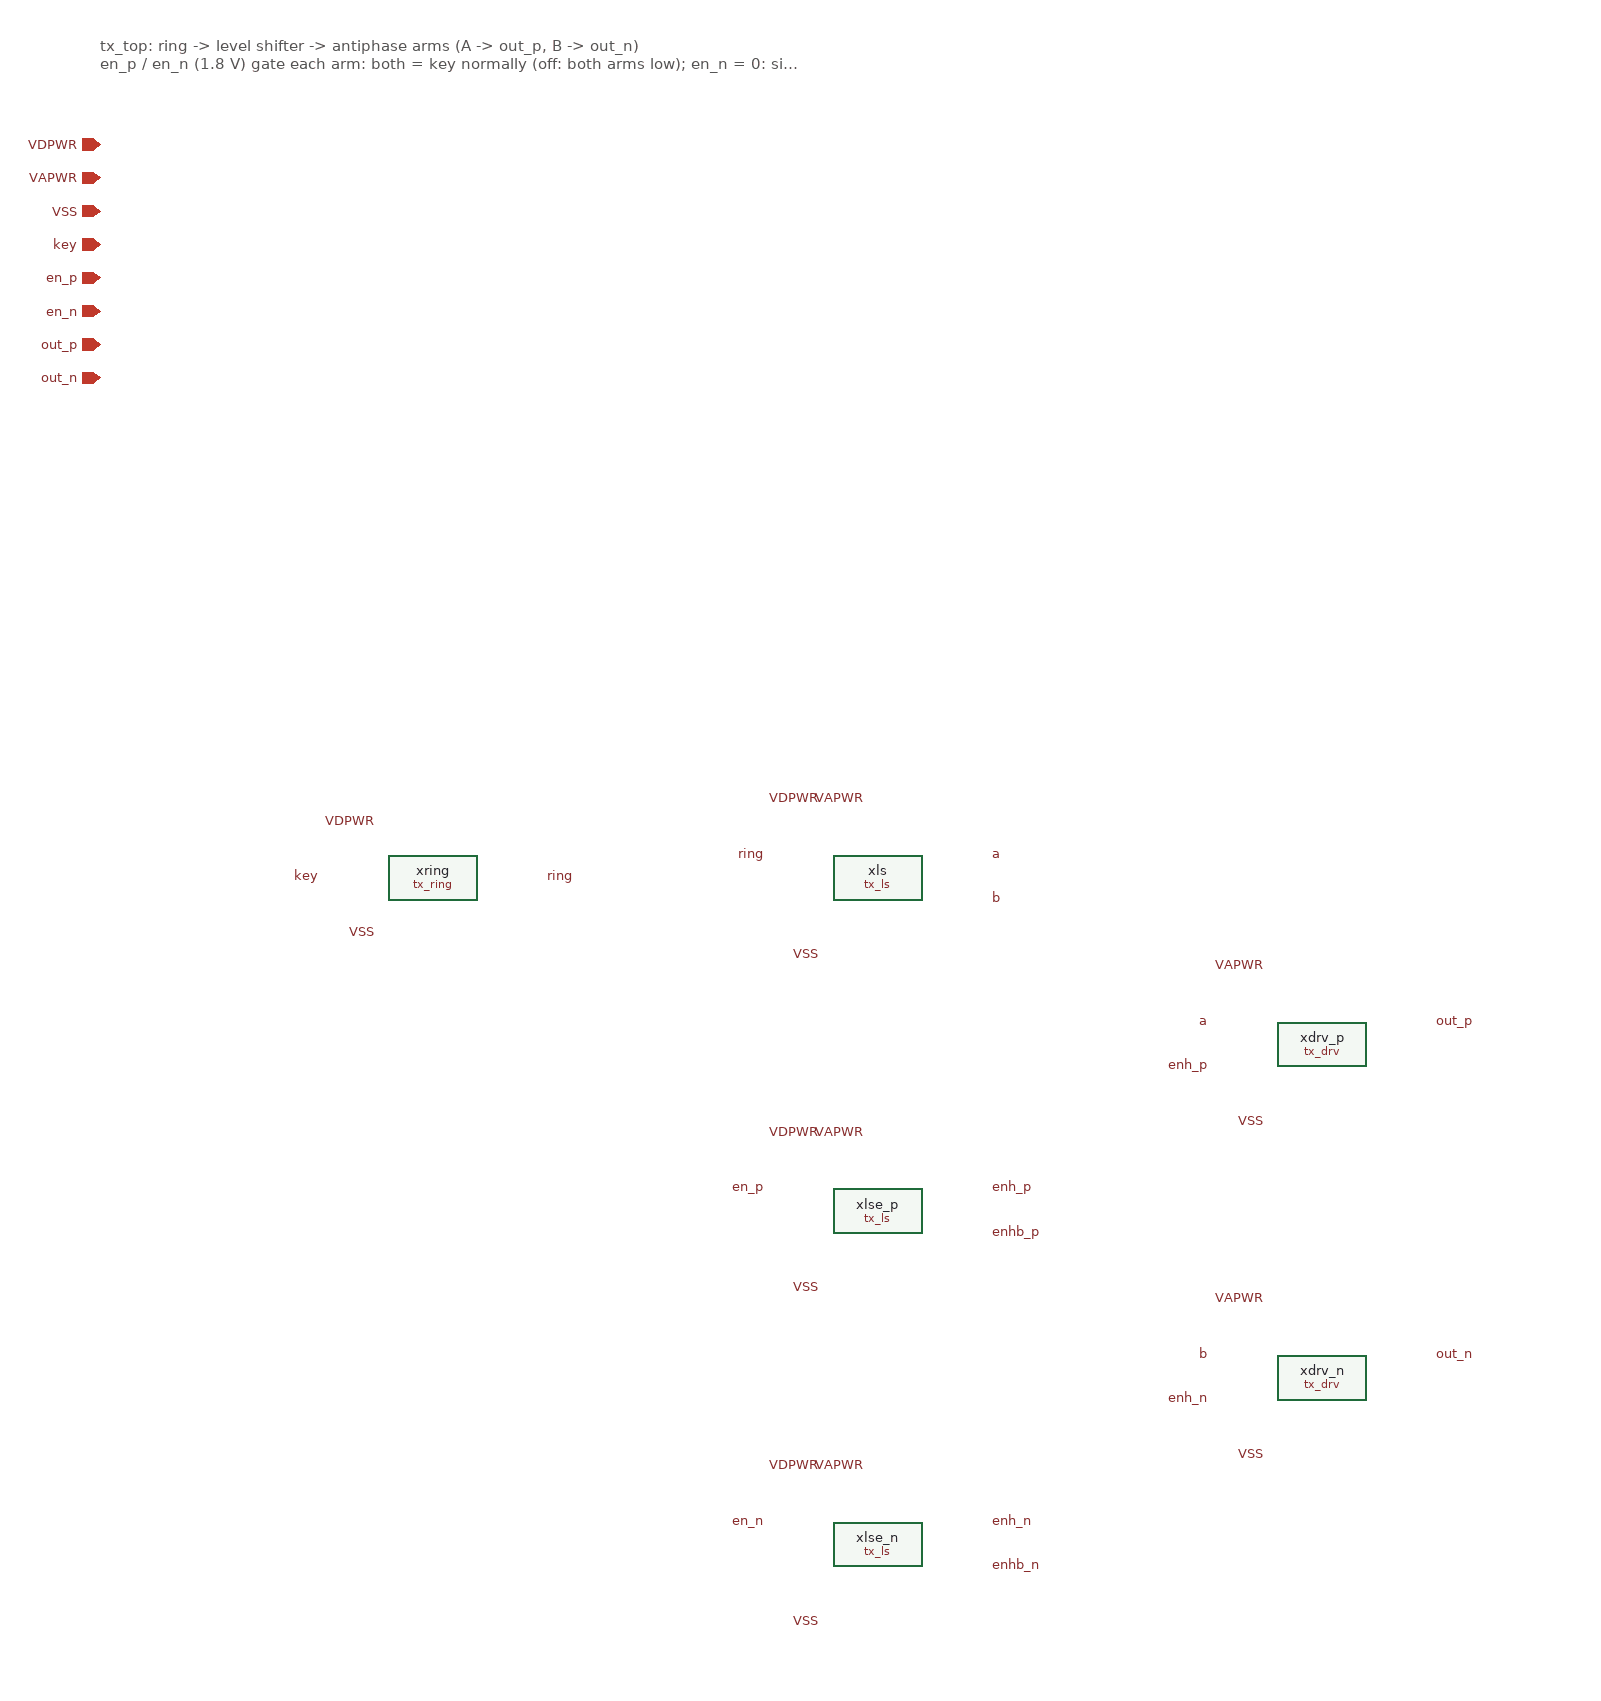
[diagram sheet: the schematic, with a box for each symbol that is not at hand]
v {xschem version=3.4.5 file_version=1.2
}
G {}
K {}
V {}
S {}
E {}
T {tx_top: ring -> level shifter -> antiphase arms (A -> out_p, B -> out_n)
en_p / en_n (1.8 V) gate each arm: both = key normally (off: both arms low); en_n = 0: single-ended fallback} -700 -760 0 0 0.4 0.4 {}
C {devices/iopin.sym} -700 -660 0 0 {name=p1
lab=VDPWR}
C {devices/iopin.sym} -700 -630 0 0 {name=p2
lab=VAPWR}
C {devices/iopin.sym} -700 -600 0 0 {name=p3
lab=VSS}
C {devices/iopin.sym} -700 -570 0 0 {name=p4
lab=key}
C {devices/iopin.sym} -700 -540 0 0 {name=p5
lab=en_p}
C {devices/iopin.sym} -700 -510 0 0 {name=p6
lab=en_n}
C {devices/iopin.sym} -700 -480 0 0 {name=p7
lab=out_p}
C {devices/iopin.sym} -700 -450 0 0 {name=p8
lab=out_n}
C {tx_ring.sym} -400 0 0 0 {name=xring}
C {devices/lab_pin.sym} -500 0 0 0 {name=p9
sig_type=std_logic
lab=key}
C {devices/lab_pin.sym} -300 0 0 1 {name=p10
sig_type=std_logic
lab=ring}
C {devices/lab_pin.sym} -450 -50 0 0 {name=p11
sig_type=std_logic
lab=VDPWR}
C {devices/lab_pin.sym} -450 50 0 0 {name=p12
sig_type=std_logic
lab=VSS}
C {tx_ls.sym} 0 0 0 0 {name=xls}
C {devices/lab_pin.sym} -100 -20 0 0 {name=p13
sig_type=std_logic
lab=ring}
C {devices/lab_pin.sym} 100 -20 0 1 {name=p14
sig_type=std_logic
lab=a}
C {devices/lab_pin.sym} 100 20 0 1 {name=p15
sig_type=std_logic
lab=b}
C {devices/lab_pin.sym} -50 -70 0 0 {name=p16
sig_type=std_logic
lab=VDPWR}
C {devices/lab_pin.sym} -10 -70 0 0 {name=p17
sig_type=std_logic
lab=VAPWR}
C {devices/lab_pin.sym} -50 70 0 0 {name=p18
sig_type=std_logic
lab=VSS}
C {tx_ls.sym} 0 300 0 0 {name=xlse_p
kn=1
kp=1
wpi=1
wni=0.42}
C {devices/lab_pin.sym} -100 280 0 0 {name=p19
sig_type=std_logic
lab=en_p}
C {devices/lab_pin.sym} 100 280 0 1 {name=p20
sig_type=std_logic
lab=enh_p}
C {devices/lab_pin.sym} 100 320 0 1 {name=p21
sig_type=std_logic
lab=enhb_p}
C {devices/lab_pin.sym} -50 230 0 0 {name=p22
sig_type=std_logic
lab=VDPWR}
C {devices/lab_pin.sym} -10 230 0 0 {name=p23
sig_type=std_logic
lab=VAPWR}
C {devices/lab_pin.sym} -50 370 0 0 {name=p24
sig_type=std_logic
lab=VSS}
C {tx_drv.sym} 400 150 0 0 {name=xdrv_p}
C {devices/lab_pin.sym} 300 130 0 0 {name=p25
sig_type=std_logic
lab=a}
C {devices/lab_pin.sym} 300 170 0 0 {name=p26
sig_type=std_logic
lab=enh_p}
C {devices/lab_pin.sym} 500 130 0 1 {name=p27
sig_type=std_logic
lab=out_p}
C {devices/lab_pin.sym} 350 80 0 0 {name=p28
sig_type=std_logic
lab=VAPWR}
C {devices/lab_pin.sym} 350 220 0 0 {name=p29
sig_type=std_logic
lab=VSS}
C {tx_ls.sym} 0 600 0 0 {name=xlse_n
kn=1
kp=1
wpi=1
wni=0.42}
C {devices/lab_pin.sym} -100 580 0 0 {name=p30
sig_type=std_logic
lab=en_n}
C {devices/lab_pin.sym} 100 580 0 1 {name=p31
sig_type=std_logic
lab=enh_n}
C {devices/lab_pin.sym} 100 620 0 1 {name=p32
sig_type=std_logic
lab=enhb_n}
C {devices/lab_pin.sym} -50 530 0 0 {name=p33
sig_type=std_logic
lab=VDPWR}
C {devices/lab_pin.sym} -10 530 0 0 {name=p34
sig_type=std_logic
lab=VAPWR}
C {devices/lab_pin.sym} -50 670 0 0 {name=p35
sig_type=std_logic
lab=VSS}
C {tx_drv.sym} 400 450 0 0 {name=xdrv_n}
C {devices/lab_pin.sym} 300 430 0 0 {name=p36
sig_type=std_logic
lab=b}
C {devices/lab_pin.sym} 300 470 0 0 {name=p37
sig_type=std_logic
lab=enh_n}
C {devices/lab_pin.sym} 500 430 0 1 {name=p38
sig_type=std_logic
lab=out_n}
C {devices/lab_pin.sym} 350 380 0 0 {name=p39
sig_type=std_logic
lab=VAPWR}
C {devices/lab_pin.sym} 350 520 0 0 {name=p40
sig_type=std_logic
lab=VSS}
